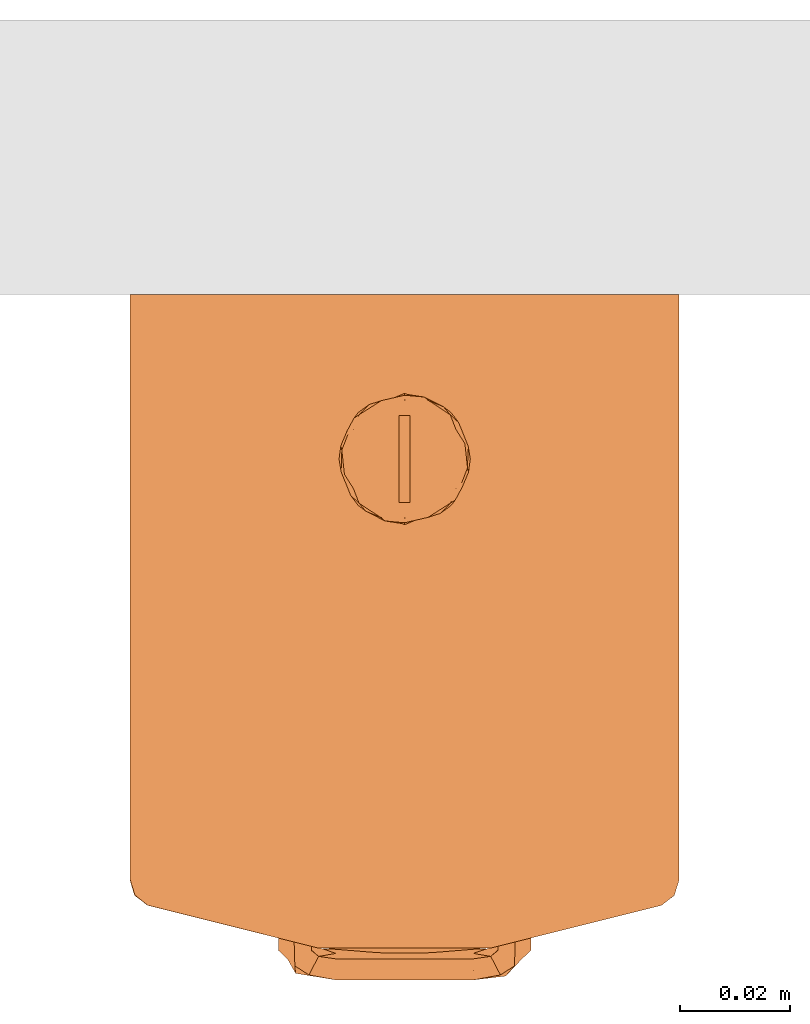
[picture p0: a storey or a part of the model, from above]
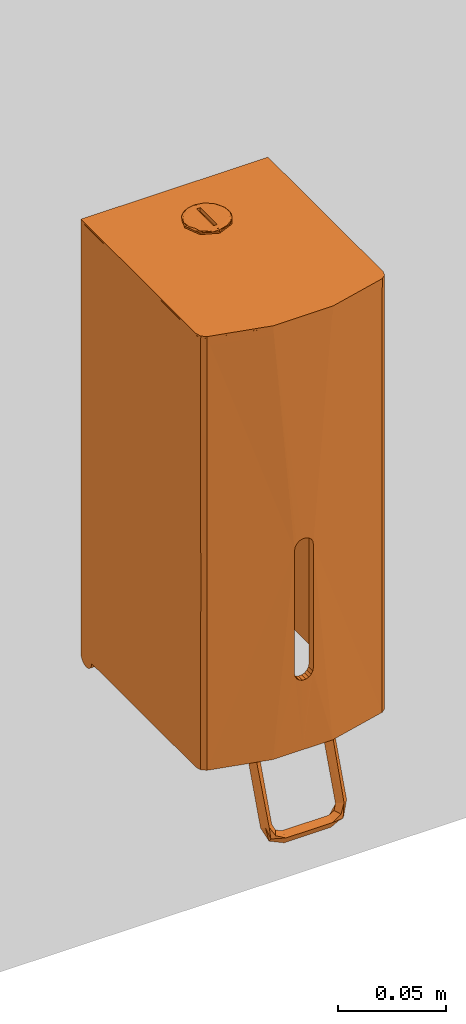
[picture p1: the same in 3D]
Properties of the parts of a building model (IFC2X3)

# File
Description: ViewDefinition [CoordinationView]
Time: 2016-09-23T08:51:37
Written by: The EXPRESS Data Manager Version 5.01.0100.02.64mod : 6 Jun 2012
Made in: 20140709_2115(x64) - Exporter 2014.0.2014.0709 - Default UI
Comment: STEP Physical File produced by: The EXPRESS Data Manager Version 5.01.0100.02.64mod : 6 Jun 2012 * Module: EDMstepFileFactory/EDMstandAlone * Creation date: Fri Sep 23 08:51:37 2016 * Host: BIM-HP * Database: C:\Users\dcole\AppData\Local\Temp\{2D2993E2-B44F-4C77-B842-F0FB1E3305FF}\ifc * Database version: 5507 * Database creation date: Fri Sep 23 08:51:35 2016 * Schema: IFC2X3 * Model: DataRepository.ifc * Model creation date: Fri Sep 23 08:51:35 2016 * Header model: DataRepository.ifc_HeaderModel * Header model creation date: Fri Sep 23 08:51:35 2016 * EDMuser: sdai-user * EDMgroup: sdai-group * License ID and type: 5605 : Permanent license. Expiry date: * EDMstepFileFactory options: 020000

# IfcProject
LongName: P:\Fastrack\53721_BELL-CHEM\ADDITIONAL DRAWINGS 2016 BIM\IFC\BC823.ifc

# IfcSite, Default
RefLatitude: 42, 24, 53, 508911; RefLongitude: -71, -15, -29, -58837; RefElevation: 0 mm

# IfcBuilding
Pset_BuildingCommon - NumberOfStoreys: 1

# IfcBuildingStorey, Level 1
LongName: Level 1; Elevation: 0 mm
Constraints - Elevation Base: Project Base Point; Elevation: 0 mm
Identity Data - Structural: no; Building Story: yes; Name: Level 1
Dimensions - Computation Height: 0 mm
Graphics - Color: 0; Symbol at End 2 Default: yes; Symbol at End 1 Default: no; Line Weight: 1; Line Pattern: -3000010

# IfcBuildingElementProxy: BC823 Dolphin Surface Mounted Soap Dispenser, BC823:BC823 Dolphin Surface Mounted Soap Dispenser:22122
In: Level 1
Material: Stainless Steel
Phasing - Phase Created: New Construction
Constraints - Level: Level: Level 1; Offset: 70.886 mm; Host: Level : Level 1; Moves With Nearby Elements: no
Dimensions - Volume: 0.000602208 m3; Height: 293mm; Width: 100mm; Projection: 121mm
Pset_ManufacturerTypeInformation - Manufacturer: Dolphin Solutions Ltd.
Pset_BuildingElementProxyCommon - Reference: BC823 Dolphin Surface Mounted Soap Dispenser
Identity Data - Description: Surface mounted soap dispenser; Address: Southpoint, Compass Park, Bodiam, Robertsbridge, TN32 5BS; Assembly Description: Other Plumbing Fixtures; Manufacturer: Dolphin Solutions Ltd.; Assembly Code: D2010900; Model: BC823; Email: info@dolphinsolutions.co.uk; Fax No.: +44 (0) 1424 205 200; URL: www.dolphinsolutions.co.uk; Tel No.: +44 (0) 1424 202 224
General - Product Data: Robust 304 grade stainless steel back plate and front. Vandal resistant metal keyed locking mechanism. 'Keyed alike' to the complete suite of Dolphin dispensers. Unique and robust inner plastic soap tank and pump assembly that resists corrosion. Clever internal design allows (only when the dispenser is unlocked) within seconds the removal and refitting of the inner pump and tank assembly for cleaning or replacement purposes. 1000ml capacity refillable dispenser. Uses Standard Liquid Hand Soap, Anti Bacterial Soap and Alcohol Hand Sanitiser (max 70% alcohol content) - this is the only surface mounted soap dispenser that we advertise that will take Alcohol Hand Saniteser!; Product Code: Same product with polished finish = BC823B Same product with white metal finish = BC823W; Product Page Link: https://www.dolphinsolutions.co.uk/product/surface-mounted-soap-dispenser/

# IfcWallStandardCase: Basic Wall:Wall 1, Basic Wall:Wall 1:3092
In: Level 1
Type - PredefinedType: STANDARD; Material: Default Wall 50 mm
Type - Analytical Properties - Absorptance: 0.1; Roughness: 1
Type - Graphics - Coarse Scale Fill Color: 8454143
Type - Construction - Function: Exterior; Width: 50 mm; Wrapping at Inserts: Do not wrap
Constraints - Top Extension Distance: 0 mm; Top Offset: 0 mm; Room Bounding: yes; Base is Attached: no; Base Offset: -94.3142 mm; Base Constraint: Level: Level 1; Top is Attached: no; Unconnected Height: 556.353 mm; Base Extension Distance: 0 mm; Location Line: Finish Face: Interior; Related to Mass: no
Dimensions - Area: 0.194723 m2; Volume: 0.00973617 m3; Length: 350 mm
Phasing - Phase Created: New Construction
Structural - Structural: no; Structural Usage: Non-bearing; Enable Analytical Model: no
Pset_WallCommon - Reference: Wall 1; LoadBearing: no; ExtendToStructure: no; IsExternal: yes
